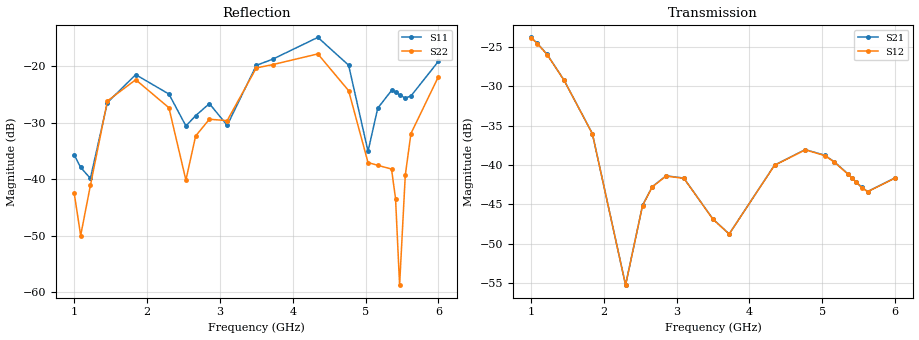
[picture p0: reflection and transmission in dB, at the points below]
!Agilent Technologies,E8364B,MY43040528,A.07.50.67
!Agilent E8364B: A.07.50.67
!Date: Sunday, March 01, 2026 21:09:02
!Correction: S11(Full 2 Port(1,2))
!S21(Full 2 Port(1,2))
!S12(Full 2 Port(1,2))
!S22(Full 2 Port(1,2))
!S2P File: Measurements: S11, S21, S12, S22:
# Hz S  dB  R 50
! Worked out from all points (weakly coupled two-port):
!   451 points, 1 GHz to 6 GHz, reference 50 ohm
!   highest |S21| = -23.77 dB at 1 GHz (marker M1); lowest = -55.3 dB at 2.3 GHz (marker M2)
!   lowest |S11| = -39.9 dB at 1.222 GHz (marker M3), VSWR 1.02, Z = 49.5 + j0.901 ohm
!   |S11| at or under -10 dB: start of sweep to end of sweep
!   |S22| runs from -58.8 to -17.0 dB; largest |S21 - S12| = 0.00024
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1e9  -35.70 58.2  -23.77 148.9  -23.80 148.9  -42.48 -8.9
1.088889e9  -37.91 80.1  -24.53 97.5  -24.56 97.5  -49.98 36.8
1.222222e9  -39.85 116.7  -25.92 20.7  -25.95 20.7  -41.10 129.7
1.455556e9  -26.40 149.4  -29.21 -110.8  -29.23 -110.8  -26.12 97.2
1.844444e9  -21.45 81.7  -36.01 38.6  -36.04 38.6  -22.35 0.2
2.3e9  -24.89 30.3  -55.26 -131.4  -55.29 -131.3  -27.32 -86.8
2.533333e9  -30.55 36.2  -45.13 166.6  -45.16 166.6  -40.16 -74.0
2.666667e9  -28.73 56.0  -42.76 96.7  -42.80 96.7  -32.33 -35.9
2.855556e9  -26.59 41.9  -41.38 -5.1  -41.42 -5.1  -29.36 -66.9
3.1e9  -30.44 57.3  -41.67 -138.0  -41.70 -138.0  -29.60 -50.9
3.5e9  -19.80 47.1  -46.89 23.5  -46.92 23.6  -20.25 -108.9
3.722222e9  -18.72 26.6  -48.78 -51.9  -48.79 -51.9  -19.68 -141.0
4.344444e9  -14.84 -44.4  -40.02 14.3  -40.05 14.3  -17.77 103.7
4.766667e9  -19.77 -109.9  -38.05 134.2  -38.08 134.2  -24.29 -8.0
5.033333e9  -35.05 -86.3  -38.76 -24.5  -38.80 -24.5  -37.04 -135.3
5.166667e9  -27.40 -42.4  -39.61 -105.5  -39.65 -105.4  -37.53 108.4
5.355556e9  -24.26 -61.7  -41.16 135.6  -41.20 135.7  -38.19 19.8
5.411111e9  -24.57 -65.9  -41.67 99.1  -41.70 99.1  -43.43 -1.3
5.466667e9  -25.05 -67.7  -42.19 61.6  -42.21 61.7  -58.78 -79.4
5.544444e9  -25.61 -62.9  -42.86 7.6  -42.89 7.6  -39.32 128.6
5.622222e9  -25.24 -54.9  -43.38 -48.1  -43.41 -48.2  -31.90 104.8
6e9  -19.08 -70.2  -41.63 43.3  -41.67 43.3  -21.79 -6.6
